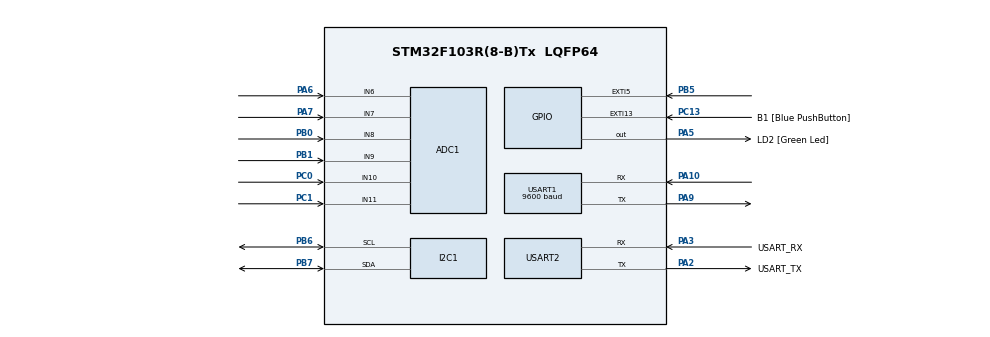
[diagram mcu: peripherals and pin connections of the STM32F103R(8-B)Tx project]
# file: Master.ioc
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ADC1.Channel-0\#ChannelRegularConversion=ADC_CHANNEL_6
ADC1.Channel-1\#ChannelRegularConversion=ADC_CHANNEL_7
ADC1.Channel-2\#ChannelRegularConversion=ADC_CHANNEL_8
ADC1.Channel-3\#ChannelRegularConversion=ADC_CHANNEL_9
ADC1.Channel-4\#ChannelRegularConversion=ADC_CHANNEL_10
ADC1.Channel-5\#ChannelRegularConversion=ADC_CHANNEL_11
ADC1.ContinuousConvMode=ENABLE
ADC1.DiscontinuousConvMode=DISABLE
ADC1.NbrOfConversion=6
ADC1.NbrOfConversionFlag=1
ADC1.Rank-0\#ChannelRegularConversion=1
ADC1.Rank-1\#ChannelRegularConversion=2
ADC1.Rank-2\#ChannelRegularConversion=3
ADC1.Rank-3\#ChannelRegularConversion=4
ADC1.Rank-4\#ChannelRegularConversion=5
ADC1.Rank-5\#ChannelRegularConversion=6
ADC1.SamplingTime-0\#ChannelRegularConversion=ADC_SAMPLETIME_239CYCLES_5
ADC1.SamplingTime-1\#ChannelRegularConversion=ADC_SAMPLETIME_239CYCLES_5
ADC1.SamplingTime-2\#ChannelRegularConversion=ADC_SAMPLETIME_239CYCLES_5
ADC1.SamplingTime-3\#ChannelRegularConversion=ADC_SAMPLETIME_239CYCLES_5
ADC1.SamplingTime-4\#ChannelRegularConversion=ADC_SAMPLETIME_239CYCLES_5
ADC1.SamplingTime-5\#ChannelRegularConversion=ADC_SAMPLETIME_239CYCLES_5
ADC1.master=1
Dma.ADC1.0.Direction=DMA_PERIPH_TO_MEMORY
Dma.ADC1.0.Instance=DMA1_Channel1
Dma.ADC1.0.MemDataAlignment=DMA_MDATAALIGN_WORD
Dma.ADC1.0.MemInc=DMA_MINC_ENABLE
Dma.ADC1.0.Mode=DMA_CIRCULAR
Dma.ADC1.0.PeriphDataAlignment=DMA_PDATAALIGN_WORD
Dma.ADC1.0.PeriphInc=DMA_PINC_DISABLE
Dma.ADC1.0.Priority=DMA_PRIORITY_LOW
Dma.Request0=ADC1
Mcu.Family=STM32F1
Mcu.Name=STM32F103R(8-B)Tx
Mcu.Package=LQFP64
NVIC.DMA1_Channel1_IRQn=true\:0\:0\:false\:false\:true\:false\:true\:true
NVIC.EXTI15_10_IRQn=true\:0\:0\:false\:false\:true\:true\:true\:true
NVIC.EXTI9_5_IRQn=true\:0\:0\:false\:false\:true\:true\:true\:true
NVIC.PriorityGroup=NVIC_PRIORITYGROUP_4
PA10.Mode=Asynchronous
PA10.Signal=USART1_RX
PA13.GPIO_Label=TMS
PA13.Mode=Serial_Wire
PA13.Signal=SYS_JTMS-SWDIO
PA14.GPIO_Label=TCK
PA14.Mode=Serial_Wire
PA14.Signal=SYS_JTCK-SWCLK
PA2.GPIO_Label=USART_TX
PA2.GPIO_Mode=GPIO_MODE_AF_PP
PA2.GPIO_PuPd=GPIO_NOPULL
PA2.GPIO_Speed=GPIO_SPEED_FREQ_LOW
PA2.Mode=Asynchronous
PA2.Signal=USART2_TX
PA3.GPIO_Label=USART_RX
PA3.GPIO_Mode=GPIO_MODE_AF_PP
PA3.GPIO_PuPd=GPIO_NOPULL
PA3.GPIO_Speed=GPIO_SPEED_FREQ_LOW
PA3.Mode=Asynchronous
PA3.Signal=USART2_RX
PA5.GPIO_Label=LD2 [Green Led]
PA5.GPIO_ModeDefaultOutputPP=GPIO_MODE_OUTPUT_PP
PA5.GPIO_PuPd=GPIO_NOPULL
PA5.GPIO_Speed=GPIO_SPEED_FREQ_LOW
PA5.Signal=GPIO_Output
PA6.Signal=ADCx_IN6
PA7.Signal=ADCx_IN7
PA9.Mode=Asynchronous
PA9.Signal=USART1_TX
PB0.Signal=ADCx_IN8
PB1.Signal=ADCx_IN9
PB3.GPIO_Label=SWO
PB3.Signal=SYS_JTDO-TRACESWO
PB5.Signal=GPXTI5
PB6.Mode=I2C
PB6.Signal=I2C1_SCL
PB7.Mode=I2C
PB7.Signal=I2C1_SDA
PC0.Signal=ADCx_IN10
PC1.Signal=ADCx_IN11
PC13-TAMPER-RTC.GPIO_Label=B1 [Blue PushButton]
PC13-TAMPER-RTC.GPIO_PuPd=GPIO_NOPULL
PC13-TAMPER-RTC.Signal=GPXTI13
PC14-OSC32_IN.Mode=LSE-External-Oscillator
PC14-OSC32_IN.Signal=RCC_OSC32_IN
PC15-OSC32_OUT.Mode=LSE-External-Oscillator
PC15-OSC32_OUT.Signal=RCC_OSC32_OUT
PD0-OSC_IN.Mode=HSE-External-Clock-Source
PD0-OSC_IN.Signal=RCC_OSC_IN
PD1-OSC_OUT.Mode=HSE-External-Clock-Source
PD1-OSC_OUT.Signal=RCC_OSC_OUT
ProjectManager.HeapSize=0x200
ProjectManager.StackSize=0x400
ProjectManager.TargetToolchain=STM32CubeIDE
RCC.ADCPresc=RCC_ADCPCLK2_DIV8
RCC.AHBFreq_Value=72000000
RCC.APB1CLKDivider=RCC_HCLK_DIV2
RCC.APB1Freq_Value=36000000
RCC.APB1TimFreq_Value=72000000
RCC.APB2Freq_Value=72000000
RCC.APB2TimFreq_Value=72000000
RCC.HCLKFreq_Value=72000000
RCC.PLLMUL=RCC_PLL_MUL9
RCC.PLLSourceVirtual=RCC_PLLSOURCE_HSE
RCC.RTCClockSelection=RCC_RTCCLKSOURCE_LSE
RCC.SYSCLKFreq_VALUE=72000000
RCC.SYSCLKSource=RCC_SYSCLKSOURCE_PLLCLK
RCC.USBFreq_Value=72000000
SH.ADCx_IN10.0=ADC1_IN10,IN10
SH.ADCx_IN11.0=ADC1_IN11,IN11
SH.ADCx_IN6.0=ADC1_IN6,IN6
SH.ADCx_IN7.0=ADC1_IN7,IN7
SH.ADCx_IN8.0=ADC1_IN8,IN8
SH.ADCx_IN9.0=ADC1_IN9,IN9
USART1.BaudRate=9600
USART1.VirtualMode=VM_ASYNC
USART2.VirtualMode=VM_ASYNC
board=NUCLEO-F103RB

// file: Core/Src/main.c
/* USER CODE BEGIN Header */
/**
  ******************************************************************************
  * @file           : main.c
  * @brief          : Main program body
  ******************************************************************************
  * @attention
  *
  * Copyright (c) 2022 STMicroelectronics.
  * All rights reserved.
  *
  * This software is licensed under terms that can be found in the LICENSE file
  * in the root directory of this software component.
  * If no LICENSE file comes with this software, it is provided AS-IS.
  *
  ******************************************************************************
  */
/* USER CODE END Header */
#include "main.h"

/* USER CODE BEGIN Includes */
#include "stdio.h"
#include "string.h"
#include "i2c-lcd.h"
/* USER CODE END Includes */

 ADC_HandleTypeDef hadc1;
DMA_HandleTypeDef hdma_adc1;

I2C_HandleTypeDef hi2c1;

UART_HandleTypeDef huart1;
UART_HandleTypeDef huart2;
DMA_HandleTypeDef hdma_usart1_rx;

/* USER CODE BEGIN PV */

//Save Joystick value
int adc_value[6];

//Change Joystick value
//0 : wheel_X / 1 : wheel_Y / 2 : step / 3~5 : servo
int motor[7];
int zero = 0;

int flag = 0;
/* USER CODE END PV */

void SystemClock_Config(void);
static void MX_GPIO_Init(void);
static void MX_USART2_UART_Init(void);
static void MX_DMA_Init(void);
static void MX_USART1_UART_Init(void);
static void MX_ADC1_Init(void);
static void MX_I2C1_Init(void);
/* USER CODE BEGIN PFP */
#ifdef __GNUC__
/* With GCC, small printf (option LD Linker->Libraries->Small printf
   set to 'Yes') calls __io_putchar() */
#define PUTCHAR_PROTOTYPE int __io_putchar(int ch)
#else
#define PUTCHAR_PROTOTYPE int fputc(int ch, FILE *f)
#endif /* __GNUC__ */

PUTCHAR_PROTOTYPE
{
  /* Place your implementation of fputc here */
  /* e.g. write a character to the USART1 and Loop until the end of transmission */
  HAL_UART_Transmit(&huart2, (uint8_t *)&ch, 1, 0xFFFF);

  return ch;
}
/* USER CODE END PFP */

/* USER CODE BEGIN 0 */
void HAL_GPIO_EXTI_Callback(uint16_t GPIO_Pin) { //Switch Interrupt
	if(GPIO_Pin == GPIO_PIN_5) flag = !flag;
}
/* USER CODE END 0 */

int main(void)
{

  /* MCU Configuration--------------------------------------------------------*/

  /* Reset of all peripherals, Initializes the Flash interface and the Systick. */
  HAL_Init();

  /* Configure the system clock */
  SystemClock_Config();

  /* Initialize all configured peripherals */
  MX_GPIO_Init();
  MX_USART2_UART_Init();
  MX_DMA_Init();
  MX_USART1_UART_Init();
  MX_ADC1_Init();
  MX_I2C1_Init();
  /* USER CODE BEGIN 2 */
  lcd_init();

  motor[6] = 3;

  HAL_ADC_Start_DMA(&hadc1, adc_value, 6);
//  HAL_UART_Transmit_DMA(&huart1, motor, 7);
  /* USER CODE END 2 */

  /* Infinite loop */
  /* USER CODE BEGIN WHILE */
  while (1)
  {
	  //wheel
//	  HAL_ADC_Start(&hadc1);
//	  HAL_ADC_PollForConversion(&hadc1, HAL_MAX_DELAY);
//	  adc_value[0] = (uint16_t)HAL_ADC_GetValue(&hadc1);
//	  HAL_ADC_Start(&hadc1);
//	  HAL_ADC_PollForConversion(&hadc1, HAL_MAX_DELAY);
//	  adc_value[1] = (uint16_t)HAL_ADC_GetValue(&hadc1);

	  if((adc_value[0] < 3500)&&(adc_value[0] > 595))	motor[0] = 0;
	  else if(adc_value[0] <= 595)						motor[0] = 1;
	  else if(adc_value[0] >= 3500)						motor[0] = 2;

	  if((adc_value[1] < 3500)&&(adc_value[1] > 595))	motor[1] = 0;
	  else if(adc_value[1] <= 595)						motor[1] = 1;
	  else if(adc_value[1] >= 3500)						motor[1] = 2;

	  //step motor
//	  HAL_ADC_Start(&hadc1);
//	  HAL_ADC_PollForConversion(&hadc1, HAL_MAX_DELAY);
//	  adc_value[2] = (uint16_t)HAL_ADC_GetValue(&hadc1);

	  if((adc_value[2] < 3500)&&(adc_value[2] > 595))	motor[2] = 0;
	  else if(adc_value[2] <= 595)						motor[2] = 1;
	  else if(adc_value[2] >= 3500)						motor[2] = 2;

	  //servo motor1
//	  HAL_ADC_Start(&hadc1);
//	  HAL_ADC_PollForConversion(&hadc1, HAL_MAX_DELAY);
//	  adc_value[3] = (uint16_t)HAL_ADC_GetValue(&hadc1);

	  if((adc_value[3] < 3500)&&(adc_value[3] > 595))	motor[3] = 0;
	  else if(adc_value[3] <= 595)						motor[3] = 1;
	  else if(adc_value[3] >= 3500)						motor[3] = 2;

	  //servo motor2
//	  HAL_ADC_Start(&hadc1);
//	  HAL_ADC_PollForConversion(&hadc1, HAL_MAX_DELAY);
//	  adc_value[4] = (uint16_t)HAL_ADC_GetValue(&hadc1);

	  if((adc_value[4] < 3500)&&(adc_value[4] > 595))	motor[4] = 0;
	  else if(adc_value[4] <= 595)						motor[4] = 1;
	  else if(adc_value[4] >= 3500)						motor[4] = 2;

	  //servo motor3
//	  HAL_ADC_Start(&hadc1);
//	  HAL_ADC_PollForConversion(&hadc1, HAL_MAX_DELAY);
//	  adc_value[5] = (uint16_t)HAL_ADC_GetValue(&hadc1);

	  if((adc_value[5] < 3500)&&(adc_value[5] > 595))	motor[5] = 0;
	  else if(adc_value[5] <= 595)						motor[5] = 1;
	  else if(adc_value[5] >= 3500)						motor[5] = 2;

	  //--------------------printf---------------------

	  //Check HAL_ADC_Start_DMA
	  printf("wheel_X : %d, wheel_Y : %d, ", adc_value[0], adc_value[1]);
	  printf("step : %d, servo1 : %d, ", adc_value[2], adc_value[3]);
	  printf("servo2 : %d, servo3 : %d\n\r\n\r", adc_value[4], adc_value[5]);

	  //Check change Joystick value
	  printf("flag : %d, ", flag);
	  printf("wheel_X : %d, wheel_Y : %d, ", motor[0], motor[1]);
	  printf("step : %d, servo1 : %d, ", motor[2], motor[3]);
	  printf("servo2 : %d, servo3 : %d\n\r\n\r", motor[4], motor[5]);

	  //----------------------lcd-----------------------

	  if(flag == 0) {
		  if((motor[0] == 0) && (motor[1] == 0)) {
			  lcd_put_cur(1, 0);
			  lcd_send_string("          ");
			  lcd_put_cur(1, 0);
			  lcd_send_string("STOP");
		  }
		  else if((motor[0] == 0) && (motor[1] == 1)) {
			  lcd_put_cur(1, 0);
			  lcd_send_string("          ");
			  lcd_put_cur(1, 0);
			  lcd_send_string("GO");
		  }
		  else if((motor[0] == 1) && (motor[1] == 0)) {
			  lcd_put_cur(1, 0);
			  lcd_send_string("          ");
			  lcd_put_cur(1, 0);
			  lcd_send_string("TURN LEFT");
		  }
		  else if((motor[0] == 2) && (motor[1] == 0)) {
			  lcd_put_cur(1, 0);
			  lcd_send_string("          ");
			  lcd_put_cur(1, 0);
			  lcd_send_string("TURN RIGHT");
		  }
		  else if((motor[0] == 0) && (motor[1] == 2)) {
			  lcd_put_cur(1, 0);
			  lcd_send_string("          ");
			  lcd_put_cur(1, 0);
			  lcd_send_string("BACK");
		  }
	  }

	  //-------------------bluetooth---------------------

	  //Master : Use sprintf -> Slave : parsing
//	  sprintf(TxBuffer, "%d#%d#%d#%d#%d#%d", wheel_X, wheel_Y, step, servo1, servo2, servo3);
//	  printf("%s\n\r\n\r", TxBuffer);
//	  HAL_UART_Transmit(&huart1, TxBuffer, TxBufferSize, 0xffff);

	  //Master : Use 6 Transmit -> Slave : Use HAL_UART_Receive_DMA
	  if(flag == 0) {
		  lcd_put_cur(0, 1);
		  lcd_send_string("      ");
		  lcd_put_cur(0, 1);
		  lcd_send_string("unlock");
		  HAL_UART_Transmit(&huart1, &motor[0], 1, 0xff);
		  HAL_UART_Transmit(&huart1, &motor[1], 1, 0xff);
		  HAL_UART_Transmit(&huart1, &zero, 1, 0xff);
		  HAL_UART_Transmit(&huart1, &zero, 1, 0xff);
		  HAL_UART_Transmit(&huart1, &zero, 1, 0xff);
		  HAL_UART_Transmit(&huart1, &zero, 1, 0xff);
		  HAL_UART_Transmit(&huart1, &motor[6], 1, 0xff);
	  }
	  else if(flag == 1) {
		  lcd_put_cur(0, 1);
		  lcd_send_string("      ");
		  lcd_put_cur(0, 1);
		  lcd_send_string("lock");
		  HAL_UART_Transmit(&huart1, &zero, 1, 0xff);
		  HAL_UART_Transmit(&huart1, &zero, 1, 0xff);
		  HAL_UART_Transmit(&huart1, &motor[2], 1, 0xff);
		  HAL_UART_Transmit(&huart1, &motor[3], 1, 0xff);
		  HAL_UART_Transmit(&huart1, &motor[4], 1, 0xff);
		  HAL_UART_Transmit(&huart1, &motor[5], 1, 0xff);
		  HAL_UART_Transmit(&huart1, &motor[6], 1, 0xff);
	  }
    /* USER CODE END WHILE */

  }
}

void SystemClock_Config(void)
{
  RCC_OscInitTypeDef RCC_OscInitStruct = {0};
  RCC_ClkInitTypeDef RCC_ClkInitStruct = {0};
  RCC_PeriphCLKInitTypeDef PeriphClkInit = {0};

  /** Initializes the RCC Oscillators according to the specified parameters
  * in the RCC_OscInitTypeDef structure.
  */
  RCC_OscInitStruct.OscillatorType = RCC_OSCILLATORTYPE_HSI;
  RCC_OscInitStruct.HSIState = RCC_HSI_ON;
  RCC_OscInitStruct.HSICalibrationValue = RCC_HSICALIBRATION_DEFAULT;
  RCC_OscInitStruct.PLL.PLLState = RCC_PLL_ON;
  RCC_OscInitStruct.PLL.PLLSource = RCC_PLLSOURCE_HSI_DIV2;
  RCC_OscInitStruct.PLL.PLLMUL = RCC_PLL_MUL16;
  if (HAL_RCC_OscConfig(&RCC_OscInitStruct) != HAL_OK)
  {
    Error_Handler();
  }

  /** Initializes the CPU, AHB and APB buses clocks
  */
  RCC_ClkInitStruct.ClockType = RCC_CLOCKTYPE_HCLK|RCC_CLOCKTYPE_SYSCLK
                              |RCC_CLOCKTYPE_PCLK1|RCC_CLOCKTYPE_PCLK2;
  RCC_ClkInitStruct.SYSCLKSource = RCC_SYSCLKSOURCE_PLLCLK;
  RCC_ClkInitStruct.AHBCLKDivider = RCC_SYSCLK_DIV1;
  RCC_ClkInitStruct.APB1CLKDivider = RCC_HCLK_DIV2;
  RCC_ClkInitStruct.APB2CLKDivider = RCC_HCLK_DIV1;

  if (HAL_RCC_ClockConfig(&RCC_ClkInitStruct, FLASH_LATENCY_2) != HAL_OK)
  {
    Error_Handler();
  }
  PeriphClkInit.PeriphClockSelection = RCC_PERIPHCLK_ADC;
  PeriphClkInit.AdcClockSelection = RCC_ADCPCLK2_DIV8;
  if (HAL_RCCEx_PeriphCLKConfig(&PeriphClkInit) != HAL_OK)
  {
    Error_Handler();
  }
}

static void MX_ADC1_Init(void)
{

  ADC_ChannelConfTypeDef sConfig = {0};

  /** Common config
  */
  hadc1.Instance = ADC1;
  hadc1.Init.ScanConvMode = ADC_SCAN_ENABLE;
  hadc1.Init.ContinuousConvMode = ENABLE;
  hadc1.Init.DiscontinuousConvMode = DISABLE;
  hadc1.Init.ExternalTrigConv = ADC_SOFTWARE_START;
  hadc1.Init.DataAlign = ADC_DATAALIGN_RIGHT;
  hadc1.Init.NbrOfConversion = 6;
  if (HAL_ADC_Init(&hadc1) != HAL_OK)
  {
    Error_Handler();
  }

  /** Configure Regular Channel
  */
  sConfig.Channel = ADC_CHANNEL_6;
  sConfig.Rank = ADC_REGULAR_RANK_1;
  sConfig.SamplingTime = ADC_SAMPLETIME_239CYCLES_5;
  if (HAL_ADC_ConfigChannel(&hadc1, &sConfig) != HAL_OK)
  {
    Error_Handler();
  }

  /** Configure Regular Channel
  */
  sConfig.Channel = ADC_CHANNEL_7;
  sConfig.Rank = ADC_REGULAR_RANK_2;
  if (HAL_ADC_ConfigChannel(&hadc1, &sConfig) != HAL_OK)
  {
    Error_Handler();
  }

  /** Configure Regular Channel
  */
  sConfig.Channel = ADC_CHANNEL_8;
  sConfig.Rank = ADC_REGULAR_RANK_3;
  if (HAL_ADC_ConfigChannel(&hadc1, &sConfig) != HAL_OK)
  {
    Error_Handler();
  }

  /** Configure Regular Channel
  */
  sConfig.Channel = ADC_CHANNEL_9;
  sConfig.Rank = ADC_REGULAR_RANK_4;
  if (HAL_ADC_ConfigChannel(&hadc1, &sConfig) != HAL_OK)
  {
    Error_Handler();
  }

  /** Configure Regular Channel
  */
  sConfig.Channel = ADC_CHANNEL_10;
  sConfig.Rank = ADC_REGULAR_RANK_5;
  if (HAL_ADC_ConfigChannel(&hadc1, &sConfig) != HAL_OK)
  {
    Error_Handler();
  }

  /** Configure Regular Channel
  */
  sConfig.Channel = ADC_CHANNEL_11;
  sConfig.Rank = ADC_REGULAR_RANK_6;
  if (HAL_ADC_ConfigChannel(&hadc1, &sConfig) != HAL_OK)
  {
    Error_Handler();
  }

}

static void MX_I2C1_Init(void)
{

  hi2c1.Instance = I2C1;
  hi2c1.Init.ClockSpeed = 100000;
  hi2c1.Init.DutyCycle = I2C_DUTYCYCLE_2;
  hi2c1.Init.OwnAddress1 = 0;
  hi2c1.Init.AddressingMode = I2C_ADDRESSINGMODE_7BIT;
  hi2c1.Init.DualAddressMode = I2C_DUALADDRESS_DISABLE;
  hi2c1.Init.OwnAddress2 = 0;
  hi2c1.Init.GeneralCallMode = I2C_GENERALCALL_DISABLE;
  hi2c1.Init.NoStretchMode = I2C_NOSTRETCH_DISABLE;
  if (HAL_I2C_Init(&hi2c1) != HAL_OK)
  {
    Error_Handler();
  }

}

static void MX_USART1_UART_Init(void)
{

  huart1.Instance = USART1;
  huart1.Init.BaudRate = 9600;
  huart1.Init.WordLength = UART_WORDLENGTH_8B;
  huart1.Init.StopBits = UART_STOPBITS_1;
  huart1.Init.Parity = UART_PARITY_NONE;
  huart1.Init.Mode = UART_MODE_TX_RX;
  huart1.Init.HwFlowCtl = UART_HWCONTROL_NONE;
  huart1.Init.OverSampling = UART_OVERSAMPLING_16;
  if (HAL_UART_Init(&huart1) != HAL_OK)
  {
    Error_Handler();
  }

}

static void MX_USART2_UART_Init(void)
{

  huart2.Instance = USART2;
  huart2.Init.BaudRate = 115200;
  huart2.Init.WordLength = UART_WORDLENGTH_8B;
  huart2.Init.StopBits = UART_STOPBITS_1;
  huart2.Init.Parity = UART_PARITY_NONE;
  huart2.Init.Mode = UART_MODE_TX_RX;
  huart2.Init.HwFlowCtl = UART_HWCONTROL_NONE;
  huart2.Init.OverSampling = UART_OVERSAMPLING_16;
  if (HAL_UART_Init(&huart2) != HAL_OK)
  {
    Error_Handler();
  }

}

static void MX_DMA_Init(void)
{

  /* DMA controller clock enable */
  __HAL_RCC_DMA1_CLK_ENABLE();

  /* DMA interrupt init */
  /* DMA1_Channel1_IRQn interrupt configuration */
  HAL_NVIC_SetPriority(DMA1_Channel1_IRQn, 0, 0);
  HAL_NVIC_EnableIRQ(DMA1_Channel1_IRQn);
  /* DMA1_Channel5_IRQn interrupt configuration */
  HAL_NVIC_SetPriority(DMA1_Channel5_IRQn, 0, 0);
  HAL_NVIC_EnableIRQ(DMA1_Channel5_IRQn);

}

static void MX_GPIO_Init(void)
{
  GPIO_InitTypeDef GPIO_InitStruct = {0};

  /* GPIO Ports Clock Enable */
  __HAL_RCC_GPIOC_CLK_ENABLE();
  __HAL_RCC_GPIOD_CLK_ENABLE();
  __HAL_RCC_GPIOA_CLK_ENABLE();
  __HAL_RCC_GPIOB_CLK_ENABLE();

  /*Configure GPIO pin Output Level */
  HAL_GPIO_WritePin(LD2_GPIO_Port, LD2_Pin, GPIO_PIN_RESET);

  /*Configure GPIO pin : B1_Pin */
  GPIO_InitStruct.Pin = B1_Pin;
  GPIO_InitStruct.Mode = GPIO_MODE_IT_RISING;
  GPIO_InitStruct.Pull = GPIO_NOPULL;
  HAL_GPIO_Init(B1_GPIO_Port, &GPIO_InitStruct);

  /*Configure GPIO pin : LD2_Pin */
  GPIO_InitStruct.Pin = LD2_Pin;
  GPIO_InitStruct.Mode = GPIO_MODE_OUTPUT_PP;
  GPIO_InitStruct.Pull = GPIO_NOPULL;
  GPIO_InitStruct.Speed = GPIO_SPEED_FREQ_LOW;
  HAL_GPIO_Init(LD2_GPIO_Port, &GPIO_InitStruct);

  /*Configure GPIO pin : PB5 */
  GPIO_InitStruct.Pin = GPIO_PIN_5;
  GPIO_InitStruct.Mode = GPIO_MODE_IT_RISING;
  GPIO_InitStruct.Pull = GPIO_NOPULL;
  HAL_GPIO_Init(GPIOB, &GPIO_InitStruct);

  /* EXTI interrupt init*/
  HAL_NVIC_SetPriority(EXTI9_5_IRQn, 0, 0);
  HAL_NVIC_EnableIRQ(EXTI9_5_IRQn);

  HAL_NVIC_SetPriority(EXTI15_10_IRQn, 0, 0);
  HAL_NVIC_EnableIRQ(EXTI15_10_IRQn);

}

void Error_Handler(void)
{
  __disable_irq();
  while (1)
  {
  }
}
